VERSION 5.7 ;
  NOWIREEXTENSIONATPIN ON ;
  DIVIDERCHAR "/" ;
  BUSBITCHARS "[]" ;
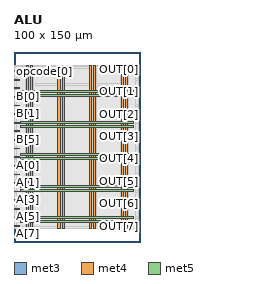
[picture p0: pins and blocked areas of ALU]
MACRO ALU
  CLASS BLOCK ;
  FOREIGN ALU ;
  ORIGIN 0.000 0.000 ;
  SIZE 100.000 BY 150.000 ;
  PIN A[0]
    DIRECTION INPUT ;
    USE SIGNAL ;
    ANTENNAGATEAREA 0.213000 ;
    PORT
      LAYER met3 ;
        RECT 0.000 59.880 4.000 60.480 ;
    END
  END A[0]
  PIN A[1]
    DIRECTION INPUT ;
    USE SIGNAL ;
    ANTENNAGATEAREA 0.213000 ;
    PORT
      LAYER met3 ;
        RECT 0.000 53.080 4.000 53.680 ;
    END
  END A[1]
  PIN A[2]
    DIRECTION INPUT ;
    USE SIGNAL ;
    ANTENNAGATEAREA 0.247500 ;
    PORT
      LAYER met3 ;
        RECT 0.000 46.280 4.000 46.880 ;
    END
  END A[2]
  PIN A[3]
    DIRECTION INPUT ;
    USE SIGNAL ;
    ANTENNAGATEAREA 0.247500 ;
    PORT
      LAYER met3 ;
        RECT 0.000 39.480 4.000 40.080 ;
    END
  END A[3]
  PIN A[4]
    DIRECTION INPUT ;
    USE SIGNAL ;
    ANTENNAGATEAREA 0.247500 ;
    PORT
      LAYER met3 ;
        RECT 0.000 32.680 4.000 33.280 ;
    END
  END A[4]
  PIN A[5]
    DIRECTION INPUT ;
    USE SIGNAL ;
    ANTENNAGATEAREA 0.213000 ;
    PORT
      LAYER met3 ;
        RECT 0.000 25.880 4.000 26.480 ;
    END
  END A[5]
  PIN A[6]
    DIRECTION INPUT ;
    USE SIGNAL ;
    ANTENNAGATEAREA 0.495000 ;
    PORT
      LAYER met3 ;
        RECT 0.000 19.080 4.000 19.680 ;
    END
  END A[6]
  PIN A[7]
    DIRECTION INPUT ;
    USE SIGNAL ;
    ANTENNAGATEAREA 0.213000 ;
    PORT
      LAYER met3 ;
        RECT 0.000 12.280 4.000 12.880 ;
    END
  END A[7]
  PIN B[0]
    DIRECTION INPUT ;
    USE SIGNAL ;
    ANTENNAGATEAREA 0.247500 ;
    PORT
      LAYER met3 ;
        RECT 0.000 114.280 4.000 114.880 ;
    END
  END B[0]
  PIN B[1]
    DIRECTION INPUT ;
    USE SIGNAL ;
    ANTENNAGATEAREA 0.495000 ;
    PORT
      LAYER met3 ;
        RECT 0.000 107.480 4.000 108.080 ;
    END
  END B[1]
  PIN B[2]
    DIRECTION INPUT ;
    USE SIGNAL ;
    ANTENNAGATEAREA 0.159000 ;
    PORT
      LAYER met3 ;
        RECT 0.000 100.680 4.000 101.280 ;
    END
  END B[2]
  PIN B[3]
    DIRECTION INPUT ;
    USE SIGNAL ;
    ANTENNAGATEAREA 0.159000 ;
    PORT
      LAYER met3 ;
        RECT 0.000 93.880 4.000 94.480 ;
    END
  END B[3]
  PIN B[4]
    DIRECTION INPUT ;
    USE SIGNAL ;
    ANTENNAGATEAREA 0.159000 ;
    PORT
      LAYER met3 ;
        RECT 0.000 87.080 4.000 87.680 ;
    END
  END B[4]
  PIN B[5]
    DIRECTION INPUT ;
    USE SIGNAL ;
    ANTENNAGATEAREA 0.247500 ;
    PORT
      LAYER met3 ;
        RECT 0.000 80.280 4.000 80.880 ;
    END
  END B[5]
  PIN B[6]
    DIRECTION INPUT ;
    USE SIGNAL ;
    ANTENNAGATEAREA 0.247500 ;
    PORT
      LAYER met3 ;
        RECT 0.000 73.480 4.000 74.080 ;
    END
  END B[6]
  PIN B[7]
    DIRECTION INPUT ;
    USE SIGNAL ;
    ANTENNAGATEAREA 0.126000 ;
    PORT
      LAYER met3 ;
        RECT 0.000 66.680 4.000 67.280 ;
    END
  END B[7]
  PIN OUT[0]
    DIRECTION OUTPUT ;
    USE SIGNAL ;
    ANTENNADIFFAREA 0.445500 ;
    PORT
      LAYER met3 ;
        RECT 96.000 136.040 100.000 136.640 ;
    END
  END OUT[0]
  PIN OUT[1]
    DIRECTION OUTPUT ;
    USE SIGNAL ;
    ANTENNADIFFAREA 0.445500 ;
    PORT
      LAYER met3 ;
        RECT 96.000 118.360 100.000 118.960 ;
    END
  END OUT[1]
  PIN OUT[2]
    DIRECTION OUTPUT ;
    USE SIGNAL ;
    ANTENNADIFFAREA 0.445500 ;
    PORT
      LAYER met3 ;
        RECT 96.000 100.680 100.000 101.280 ;
    END
  END OUT[2]
  PIN OUT[3]
    DIRECTION OUTPUT ;
    USE SIGNAL ;
    ANTENNADIFFAREA 0.445500 ;
    PORT
      LAYER met3 ;
        RECT 96.000 83.000 100.000 83.600 ;
    END
  END OUT[3]
  PIN OUT[4]
    DIRECTION OUTPUT ;
    USE SIGNAL ;
    ANTENNADIFFAREA 0.445500 ;
    PORT
      LAYER met3 ;
        RECT 96.000 65.320 100.000 65.920 ;
    END
  END OUT[4]
  PIN OUT[5]
    DIRECTION OUTPUT ;
    USE SIGNAL ;
    ANTENNADIFFAREA 0.445500 ;
    PORT
      LAYER met3 ;
        RECT 96.000 47.640 100.000 48.240 ;
    END
  END OUT[5]
  PIN OUT[6]
    DIRECTION OUTPUT ;
    USE SIGNAL ;
    ANTENNADIFFAREA 0.445500 ;
    PORT
      LAYER met3 ;
        RECT 96.000 29.960 100.000 30.560 ;
    END
  END OUT[6]
  PIN OUT[7]
    DIRECTION OUTPUT ;
    USE SIGNAL ;
    ANTENNADIFFAREA 1.782000 ;
    PORT
      LAYER met3 ;
        RECT 96.000 12.280 100.000 12.880 ;
    END
  END OUT[7]
  PIN VGND
    DIRECTION INOUT ;
    USE GROUND ;
    PORT
      LAYER met4 ;
        RECT 13.020 10.640 14.620 138.960 ;
    END
    PORT
      LAYER met4 ;
        RECT 38.020 10.640 39.620 138.960 ;
    END
    PORT
      LAYER met4 ;
        RECT 63.020 10.640 64.620 138.960 ;
    END
    PORT
      LAYER met4 ;
        RECT 88.020 10.640 89.620 138.960 ;
    END
    PORT
      LAYER met5 ;
        RECT 5.280 18.380 94.540 19.980 ;
    END
    PORT
      LAYER met5 ;
        RECT 5.280 43.380 94.540 44.980 ;
    END
    PORT
      LAYER met5 ;
        RECT 5.280 68.380 94.540 69.980 ;
    END
    PORT
      LAYER met5 ;
        RECT 5.280 93.380 94.540 94.980 ;
    END
    PORT
      LAYER met5 ;
        RECT 5.280 118.380 94.540 119.980 ;
    END
  END VGND
  PIN VPWR
    DIRECTION INOUT ;
    USE POWER ;
    PORT
      LAYER met4 ;
        RECT 9.720 10.640 11.320 138.960 ;
    END
    PORT
      LAYER met4 ;
        RECT 34.720 10.640 36.320 138.960 ;
    END
    PORT
      LAYER met4 ;
        RECT 59.720 10.640 61.320 138.960 ;
    END
    PORT
      LAYER met4 ;
        RECT 84.720 10.640 86.320 138.960 ;
    END
    PORT
      LAYER met5 ;
        RECT 5.280 15.080 94.540 16.680 ;
    END
    PORT
      LAYER met5 ;
        RECT 5.280 40.080 94.540 41.680 ;
    END
    PORT
      LAYER met5 ;
        RECT 5.280 65.080 94.540 66.680 ;
    END
    PORT
      LAYER met5 ;
        RECT 5.280 90.080 94.540 91.680 ;
    END
    PORT
      LAYER met5 ;
        RECT 5.280 115.080 94.540 116.680 ;
    END
  END VPWR
  PIN opcode[0]
    DIRECTION INPUT ;
    USE SIGNAL ;
    ANTENNAGATEAREA 0.159000 ;
    PORT
      LAYER met3 ;
        RECT 0.000 134.680 4.000 135.280 ;
    END
  END opcode[0]
  PIN opcode[1]
    DIRECTION INPUT ;
    USE SIGNAL ;
    ANTENNAGATEAREA 0.213000 ;
    PORT
      LAYER met3 ;
        RECT 0.000 127.880 4.000 128.480 ;
    END
  END opcode[1]
  PIN opcode[2]
    DIRECTION INPUT ;
    USE SIGNAL ;
    ANTENNAGATEAREA 0.247500 ;
    PORT
      LAYER met3 ;
        RECT 0.000 121.080 4.000 121.680 ;
    END
  END opcode[2]
  OBS
      LAYER nwell ;
        RECT 5.330 10.795 94.490 138.910 ;
      LAYER li1 ;
        RECT 5.520 10.795 94.300 138.805 ;
      LAYER met1 ;
        RECT 0.530 10.640 97.910 138.960 ;
      LAYER met2 ;
        RECT 0.550 10.695 97.890 138.905 ;
      LAYER met3 ;
        RECT 0.525 137.040 97.915 138.885 ;
        RECT 0.525 135.680 95.600 137.040 ;
        RECT 4.400 135.640 95.600 135.680 ;
        RECT 4.400 134.280 97.915 135.640 ;
        RECT 0.525 128.880 97.915 134.280 ;
        RECT 4.400 127.480 97.915 128.880 ;
        RECT 0.525 122.080 97.915 127.480 ;
        RECT 4.400 120.680 97.915 122.080 ;
        RECT 0.525 119.360 97.915 120.680 ;
        RECT 0.525 117.960 95.600 119.360 ;
        RECT 0.525 115.280 97.915 117.960 ;
        RECT 4.400 113.880 97.915 115.280 ;
        RECT 0.525 108.480 97.915 113.880 ;
        RECT 4.400 107.080 97.915 108.480 ;
        RECT 0.525 101.680 97.915 107.080 ;
        RECT 4.400 100.280 95.600 101.680 ;
        RECT 0.525 94.880 97.915 100.280 ;
        RECT 4.400 93.480 97.915 94.880 ;
        RECT 0.525 88.080 97.915 93.480 ;
        RECT 4.400 86.680 97.915 88.080 ;
        RECT 0.525 84.000 97.915 86.680 ;
        RECT 0.525 82.600 95.600 84.000 ;
        RECT 0.525 81.280 97.915 82.600 ;
        RECT 4.400 79.880 97.915 81.280 ;
        RECT 0.525 74.480 97.915 79.880 ;
        RECT 4.400 73.080 97.915 74.480 ;
        RECT 0.525 67.680 97.915 73.080 ;
        RECT 4.400 66.320 97.915 67.680 ;
        RECT 4.400 66.280 95.600 66.320 ;
        RECT 0.525 64.920 95.600 66.280 ;
        RECT 0.525 60.880 97.915 64.920 ;
        RECT 4.400 59.480 97.915 60.880 ;
        RECT 0.525 54.080 97.915 59.480 ;
        RECT 4.400 52.680 97.915 54.080 ;
        RECT 0.525 48.640 97.915 52.680 ;
        RECT 0.525 47.280 95.600 48.640 ;
        RECT 4.400 47.240 95.600 47.280 ;
        RECT 4.400 45.880 97.915 47.240 ;
        RECT 0.525 40.480 97.915 45.880 ;
        RECT 4.400 39.080 97.915 40.480 ;
        RECT 0.525 33.680 97.915 39.080 ;
        RECT 4.400 32.280 97.915 33.680 ;
        RECT 0.525 30.960 97.915 32.280 ;
        RECT 0.525 29.560 95.600 30.960 ;
        RECT 0.525 26.880 97.915 29.560 ;
        RECT 4.400 25.480 97.915 26.880 ;
        RECT 0.525 20.080 97.915 25.480 ;
        RECT 4.400 18.680 97.915 20.080 ;
        RECT 0.525 13.280 97.915 18.680 ;
        RECT 4.400 11.880 95.600 13.280 ;
        RECT 0.525 10.715 97.915 11.880 ;
      LAYER met4 ;
        RECT 2.135 12.415 9.320 137.185 ;
        RECT 11.720 12.415 12.620 137.185 ;
        RECT 15.020 12.415 34.320 137.185 ;
        RECT 36.720 12.415 37.620 137.185 ;
        RECT 40.020 12.415 59.320 137.185 ;
        RECT 61.720 12.415 62.620 137.185 ;
        RECT 65.020 12.415 84.320 137.185 ;
        RECT 86.720 12.415 87.620 137.185 ;
        RECT 90.020 12.415 96.305 137.185 ;
      LAYER met5 ;
        RECT 17.140 123.300 84.060 124.900 ;
  END
END ALU
END LIBRARY

